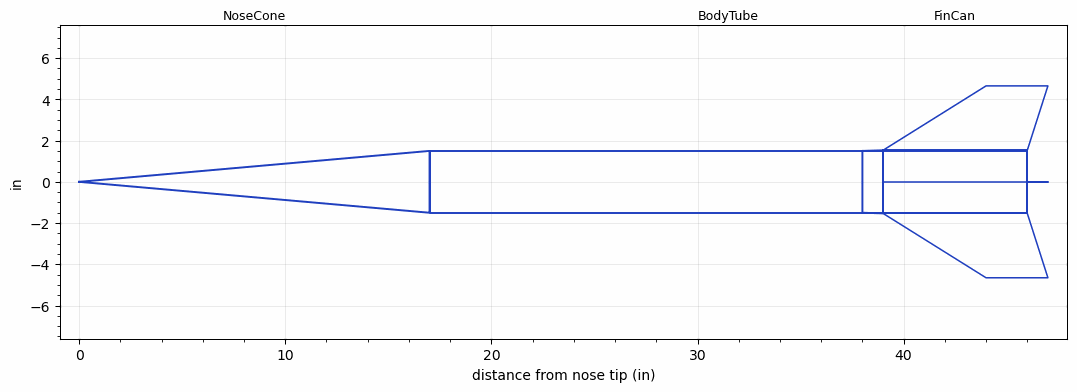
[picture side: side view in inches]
<RASAeroDocument>
 <FileVersion>2</FileVersion>
 <RocketDesign>
  <NoseCone>
   <Length>17</Length>
   <Diameter>3</Diameter>
   <Shape>Conical</Shape>
   <Location>0</Location>
  </NoseCone>
  <BodyTube>
   <Length>29</Length>
   <Diameter>3</Diameter>
   <Location>17</Location>
  </BodyTube>
  <FinCan>
   <Length>7</Length>
   <Diameter>3.06</Diameter>
   <InsideDiameter>3</InsideDiameter>
   <Location>46</Location>
   <ShoulderLength>1</ShoulderLength>
   <Offset>-7</Offset>
   <Fin>
    <Count>4</Count>
    <Chord>7</Chord>
    <Span>3.125</Span>
    <SweepDistance>5</SweepDistance>
    <TipChord>3</TipChord>
    <Thickness>0.15</Thickness>
    <LERadius>0.02</LERadius>
    <Location>7</Location>
    <AirfoilSection>Hexagonal</AirfoilSection>
    <FX1>0.75</FX1>
    <FX3>0.75</FX3>
   </Fin>
  </FinCan>
  <Surface>Camouflage Paint</Surface>
  <ModifiedBarrowman>True</ModifiedBarrowman>
  <Turbulence>True</Turbulence>
  <UseBooster1>False</UseBooster1>
  <UseBooster2>False</UseBooster2>
 </RocketDesign>
 <LaunchSite>
  <Altitude>2000</Altitude>
  <Pressure>0</Pressure>
  <RodAngle>2</RodAngle>
  <RodLength>10</RodLength>
  <Temperature>75</Temperature>
  <WindSpeed>7</WindSpeed>
 </LaunchSite>
 <Recovery>
  <Altitude1>1000</Altitude1>
  <Altitude2>1000</Altitude2>
  <DeviceType1>None</DeviceType1>
  <DeviceType2>None</DeviceType2>
  <Event1>False</Event1>
  <Event2>False</Event2>
  <Size1>1</Size1>
  <Size2>1</Size2>
  <EventType1>None</EventType1>
  <EventType2>None</EventType2>
  <CD1>1.33</CD1>
  <CD2>1.33</CD2>
 </Recovery>
 <SimulationList>
  <Simulation>
   <SustainerEngine>M2050  (AT)</SustainerEngine>
   <SustainerLaunchWt>12.2</SustainerLaunchWt>
   <SustainerNozzleDiameter>1.875</SustainerNozzleDiameter>
   <SustainerCG>30.3</SustainerCG>
   <SustainerIgnitionDelay>0</SustainerIgnitionDelay>
   <Booster1SeparationDelay>0</Booster1SeparationDelay>
   <Booster1IgnitionDelay>0</Booster1IgnitionDelay>
   <IncludeBooster1>False</IncludeBooster1>
   <Booster2Delay>0</Booster2Delay>
   <IncludeBooster2>False</IncludeBooster2>
   <TimetoApogee>34.14028</TimetoApogee>
   <MaxAltitude>29513.17</MaxAltitude>
   <MaxVelocity>3405.361</MaxVelocity>
  </Simulation>
 </SimulationList>
</RASAeroDocument>
